VERSION 5.8 ;
BUSBITCHARS "[]" ;
DIVIDERCHAR "/" ;

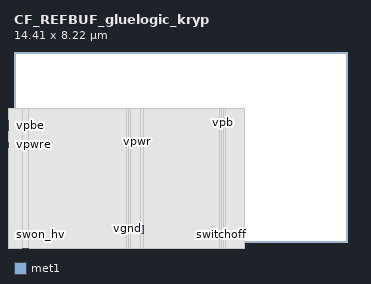
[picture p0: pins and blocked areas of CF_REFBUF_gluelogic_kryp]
MACRO CF_REFBUF_gluelogic_kryp
  ORIGIN -4.42 -2.465 ;
  SIZE 14.41 BY 8.22 ;
  PIN swon_hv
    DIRECTION INPUT ;
    USE SIGNAL ;
    PORT
      LAYER met1 ;
        RECT 4.77 0.485 5.06 0.69 ;
    END
  END swon_hv
  PIN switchoff
    DIRECTION OUTPUT ;
    USE SIGNAL ;
    PORT
      LAYER met1 ;
        RECT 13.32 2.575 13.505 2.89 ;
    END
  END switchoff
  PIN vnb
    DIRECTION INPUT ;
    USE GROUND ;
    PORT
      LAYER met1 ;
        RECT 9.91 2.835 10.025 3.18 ;
    END
  END vnb
  PIN vgnd
    DIRECTION INPUT ;
    USE GROUND ;
    PORT
      LAYER met1 ;
        RECT 9.275 2.855 9.385 3.21 ;
    END
  END vgnd
  PIN vpb
    DIRECTION INPUT ;
    USE POWER ;
    PORT
      LAYER met1 ;
        RECT 13.385 7.48 13.56 7.815 ;
    END
  END vpb
  PIN vpwr
    DIRECTION INPUT ;
    USE POWER ;
    PORT
      LAYER met1 ;
        RECT 9.48 6.7 10.02 6.895 ;
    END
  END vpwr
  PIN vpbe
    DIRECTION INPUT ;
    USE POWER ;
    PORT
      LAYER met1 ;
        RECT 0.42 7.29 0.575 7.705 ;
    END
  END vpbe
  PIN vpwre
    DIRECTION INPUT ;
    USE POWER ;
    PORT
      LAYER met1 ;
        RECT 1.165 6.575 1.7 6.76 ;
    END
  END vpwre
  OBS
    LAYER li1 ;
      RECT 0 0 14.41 8.22 ;
    LAYER met1 ;
      RECT 0 0 0.42 8.22 ;
      RECT 0.42 0 0.575 7.29 ;
      RECT 0.42 7.705 0.575 8.22 ;
      RECT 0.575 0 1.165 8.22 ;
      RECT 1.165 0 1.7 6.575 ;
      RECT 1.165 6.76 1.7 8.22 ;
      RECT 1.7 0 4.77 8.22 ;
      RECT 4.77 0 5.06 0.485 ;
      RECT 4.77 0.69 5.06 8.22 ;
      RECT 5.06 0 9.275 8.22 ;
      RECT 9.275 0 9.385 2.855 ;
      RECT 9.275 3.21 9.385 8.22 ;
      RECT 9.385 0 9.48 8.22 ;
      RECT 9.48 0 9.91 6.7 ;
      RECT 9.48 6.895 9.91 8.22 ;
      RECT 9.91 0 10.02 2.835 ;
      RECT 9.91 3.18 10.02 6.7 ;
      RECT 9.91 6.895 10.02 8.22 ;
      RECT 10.02 0 10.025 2.835 ;
      RECT 10.02 3.18 10.025 8.22 ;
      RECT 10.025 0 13.32 8.22 ;
      RECT 13.32 0 13.385 2.575 ;
      RECT 13.32 2.89 13.385 8.22 ;
      RECT 13.385 0 13.505 2.575 ;
      RECT 13.385 2.89 13.505 7.48 ;
      RECT 13.385 7.815 13.505 8.22 ;
      RECT 13.505 0 13.56 7.48 ;
      RECT 13.505 7.815 13.56 8.22 ;
      RECT 13.56 0 14.41 8.22 ;
  END
END CF_REFBUF_gluelogic_kryp

END LIBRARY
